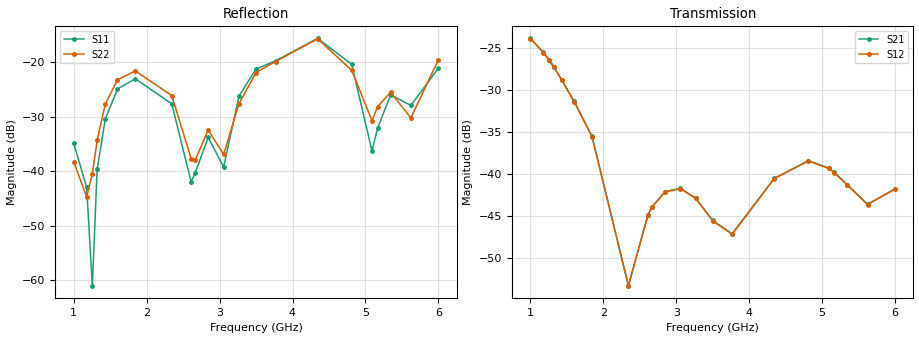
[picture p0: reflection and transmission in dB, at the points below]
!Agilent Technologies,E8364B,MY43040528,A.07.50.67
!Agilent E8364B: A.07.50.67
!Date: Sunday, March 01, 2026 16:51:05
!Correction: S11(Full 2 Port(1,2))
!S21(Full 2 Port(1,2))
!S12(Full 2 Port(1,2))
!S22(Full 2 Port(1,2))
!S2P File: Measurements: S11, S21, S12, S22:
# Hz S  dB  R 50
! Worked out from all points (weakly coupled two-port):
!   451 points, 1 GHz to 6 GHz, reference 50 ohm
!   highest |S21| = -23.90 dB at 1 GHz (marker M1); lowest = -53.3 dB at 2.344 GHz (marker M2)
!   lowest |S11| = -61.0 dB at 1.256 GHz (marker M3), VSWR 1.00, Z = 49.9 + j0.0649 ohm
!   |S11| at or under -10 dB: start of sweep to end of sweep
!   |S22| runs from -44.8 to -15.6 dB; largest |S21 - S12| = 0.00029
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1e9  -34.85 26.8  -23.90 152.9  -23.94 152.9  -38.27 -14.1
1.177778e9  -43.01 35.6  -25.54 51.3  -25.58 51.4  -44.73 59.8
1.255556e9  -61.04 132.9  -26.43 7.2  -26.47 7.3  -40.54 112.0
1.322222e9  -39.65 -172.8  -27.28 -30.3  -27.33 -30.3  -34.32 114.0
1.433333e9  -30.46 162.4  -28.87 -91.6  -28.90 -91.6  -27.72 94.2
1.6e9  -24.94 125.0  -31.37 178.6  -31.42 178.6  -23.23 51.9
1.844444e9  -23.05 76.5  -35.53 48.3  -35.56 48.4  -21.62 -7.5
2.344444e9  -27.66 3.3  -53.28 -150.3  -53.26 -150.4  -26.13 -107.1
2.611111e9  -42.01 13.5  -44.90 132.4  -44.94 132.5  -37.74 -120.0
2.666667e9  -40.27 52.3  -43.93 104.5  -43.96 104.6  -37.95 -92.5
2.844444e9  -33.83 51.1  -42.11 11.7  -42.15 11.8  -32.47 -95.1
3.055556e9  -39.24 80.3  -41.71 -100.7  -41.75 -100.6  -36.94 -101.9
3.266667e9  -26.22 101.1  -42.88 148.6  -42.92 148.8  -27.62 -72.5
3.5e9  -21.28 62.4  -45.53 37.1  -45.58 37.2  -21.92 -120.0
3.766667e9  -19.76 33.3  -47.11 -65.8  -47.18 -65.7  -19.89 -161.4
4.344444e9  -15.64 -41.7  -40.52 23.2  -40.55 23.3  -15.73 100.0
4.811111e9  -20.40 -120.5  -38.42 121.4  -38.47 121.4  -21.50 8.7
5.088889e9  -36.28 -106.3  -39.31 -43.1  -39.35 -43.1  -30.75 28.3
5.166667e9  -32.13 -59.4  -39.82 -90.1  -39.86 -90.1  -28.15 36.2
5.344444e9  -26.01 -72.0  -41.27 159.2  -41.32 159.2  -25.54 12.6
5.622222e9  -27.96 -80.1  -43.61 -30.4  -43.65 -30.3  -30.24 14.2
6e9  -21.10 -80.4  -41.76 60.3  -41.80 60.3  -19.56 -16.9
